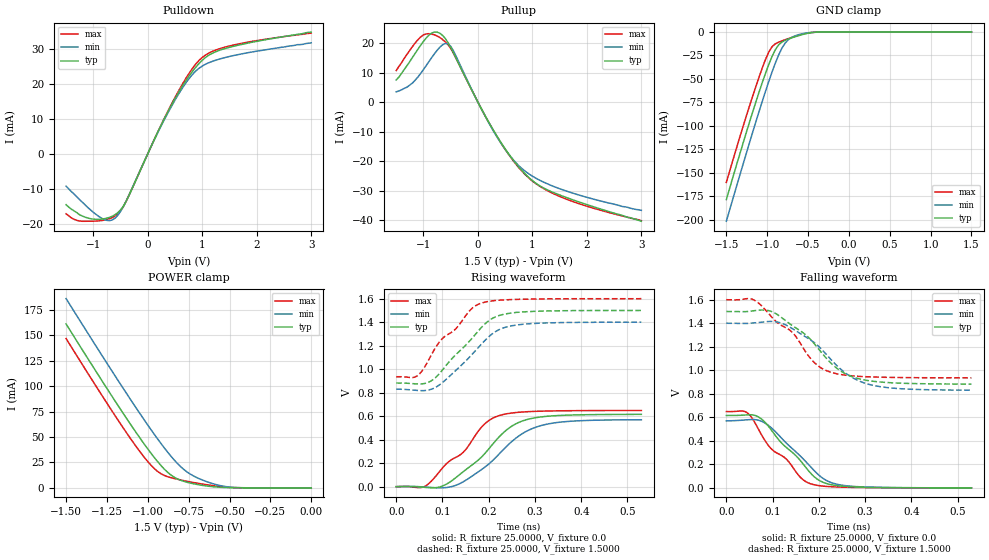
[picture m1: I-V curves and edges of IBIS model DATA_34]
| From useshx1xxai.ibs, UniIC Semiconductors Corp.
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|When TDQS is enabled, NU_TDQS is a output with terminal resistance;
|When TDQS is disabled, NU_TDQS is a DM;
|   Model DATA_34
[Model]  DATA_34
Model_type   I/O
Polarity   Non-Inverting
Enable   Active-High
Vinl =   0.600000V
Vinh =   0.900000V
Vmeas =   0.750000V
Rref =   25.0000000
Vref =   0.7500000V
C_comp   1.3900pF   1.3640pF   1.5600pF
[Temperature Range]   25.0000   95.0000   -40.0000
[Voltage Range]   1.5000V   1.4000V   1.6000V
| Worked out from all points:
|   slope of the pulldown table from 0 to 0.225 V, typ, clamps not added: 29.8 ohm
|   slope of the pullup table from 0 to 0.225 V, typ, clamps not added: 29.6 ohm
|   GND clamp passes 1 mA (typ) near -0.48 V on its own axis
|   POWER clamp passes 1 mA (typ) near -0.59 V on its own axis
|   rising waveform, R_fixture 25.0000, V_fixture 0.0: 20-80 % time 98.2ps typ, 102ps min, 93.5ps max; typ from 0 V to 0.615 V
|   rising waveform, R_fixture 25.0000, V_fixture 1.5000: 20-80 % time 86.9ps typ, 86.6ps min, 83.7ps max; typ from 0.882 V to 1.5 V
|   falling waveform, R_fixture 25.0000, V_fixture 0.0: 20-80 % time 85.5ps typ, 86.9ps min, 85ps max; typ from 0.615 V to 0 V
|   falling waveform, R_fixture 25.0000, V_fixture 1.5000: 20-80 % time 99ps typ, 99.1ps min, 94.7ps max; typ from 1.5 V to 0.882 V
[Pulldown]
|Voltage   I(typ)   I(min)   I(max)
-1.5V     -14.6mA    -9.3mA     -17.2mA
-1.3V     -16.9mA    -12.4mA    -19.1mA
-1.1V     -18.42mA   -15.42mA   -19.33mA
-850mV    -18.72mA   -18.45mA   -19.14mA
-650mV    -17.88mA   -18.95mA   -18.26mA
-400mV    -13.69mA   -13.63mA   -13.73mA
150mV     5.101mA    4.945mA    5.116mA
500mV     15.78mA    15.34mA    16.1mA
750mV     22.05mA    21.34mA    22.8mA
950mV     25.95mA    24.55mA    26.84mA
1.45V     30.22mA    27.62mA    30.62mA
3V        34.8mA     31.7mA     34.5mA
[Pullup]
|Voltage   I(typ)   I(min)   I(max)
-1.5V     7.5mA      3.5mA      10.7mA
-1.2V     15.18mA    6.5mA      18.86mA
-1V       20.55mA    11.03mA    22.75mA
-750mV    23.71mA    17.52mA    22.4mA
-550mV    20.17mA    19.79mA    19.47mA
-450mV    16.69mA    17.37mA    16.58mA
300mV     -9.979mA   -10.24mA   -10.09mA
550mV     -17.14mA   -17.23mA   -17.31mA
800mV     -23mA      -22.34mA   -23.2mA
1.1V      -27.91mA   -26.09mA   -28.02mA
1.55V     -31.76mA   -29.61mA   -32.28mA
3V        -40.3mA    -36.6mA    -40.1mA
[GND_clamp]
|Voltage   I(typ)   I(min)   I(max)
-1.5V     -178.7mA   -201.8mA   -160.4mA
-1.22V    -97.06mA   -119mA     -79.82mA
-1.1V     -64.25mA   -84.88mA   -48.13mA
-1.02V    -43.87mA   -63.01mA   -29.1mA
-980mV    -34.46mA   -52.52mA   -21.22mA
-940mV    -25.94mA   -42.47mA   -15.57mA
-900mV    -18.8mA    -33.04mA   -12.54mA
-820mV    -10.64mA   -17.25mA   -9.468mA
-740mV    -7.413mA   -8.071mA   -6.938mA
-620mV    -3.934mA   -2.917mA   -3.522mA
-420mV    -302.4uA   -187.9uA   -208.3uA
1.5V      1.623nA    17.64nA    235.2pA
[POWER_clamp]
|Voltage   I(typ)   I(min)   I(max)
-1.5V     161.3mA    186.3mA    147mA
-1.22V    90.37mA    115.2mA    75.9mA
-1.04V    47.2mA     71.18mA    33.88mA
-980mV    33.96mA    57.17mA    22.22mA
-940mV    25.82mA    48.16mA    16.16mA
-880mV    15.49mA    35.42mA    11.04mA
-840mV    10.61mA    27.72mA    9.264mA
-780mV    6.409mA    18.15mA    7.115mA
-720mV    3.991mA    11.66mA    5.224mA
-560mV    586.1uA    2.318mA    1.296mA
-440mV    47uA       184.9uA    109.8uA
0V        1.623nA    5.301nA    289pA
[Ramp]
| variable   typ   min   max
dV/dt_r  0.3694/99.9524p   0.3422/0.1029n   0.3891/94.7830p
dV/dt_f  0.3712/0.1005n   0.3425/0.1006n   0.3991/96.2412p
R_load = 25.0000
[Rising Waveform]
R_fixture= 25.0000
V_fixture= 0.0
V_fixture_min= 0.0
V_fixture_max= 0.0
|time   V(typ)   V(min)   V(max)
0s        0V         0V         0V
60ps      -5.059mV   -2.656mV   -859.5uV
105ps     13.96mV    -8.608mV   181.2mV
150ps     143.2mV    53.69mV    314.4mV
190ps     275.1mV    161.4mV    529.6mV
225ps     433.6mV    288.3mV    607.6mV
265ps     546.6mV    431.1mV    632.9mV
320ps     596.5mV    526.6mV    643mV
390ps     610.7mV    559.7mV    646.7mV
530ps     615.1mV    569.3mV    648.3mV
[Rising Waveform]
R_fixture= 25.0000
V_fixture= 1.5000
V_fixture_min= 1.4000
V_fixture_max= 1.6000
|time   V(typ)   V(min)   V(max)
0s        882.1mV    830.4mV    935.2mV
45ps      874mV      819mV      941.6mV
75ps      898.8mV    827.8mV    1.114V
100ps     992.8mV    885.7mV    1.261V
130ps     1.127V     993.3mV    1.348V
165ps     1.267V     1.13V      1.521V
185ps     1.358V     1.216V     1.563V
220ps     1.453V     1.331V     1.586V
265ps     1.484V     1.378V     1.594V
530ps     1.5V       1.4V       1.6V
[Falling Waveform]
R_fixture= 25.0000
V_fixture= 0.0
V_fixture_min= 0.0
V_fixture_max= 0.0
|time   V(typ)   V(min)   V(max)
0s        615.1mV    569.3mV    648.3mV
45ps      620.4mV    578.5mV    638.9mV
75ps      588.4mV    567.5mV    458.6mV
100ps     477.1mV    500.9mV    321mV
130ps     342.3mV    379.5mV    243.2mV
165ps     207.8mV    250.9mV    71.54mV
185ps     113.1mV    167mV      31.06mV
215ps     38.58mV    65.59mV    12.58mV
255ps     12.74mV    19.75mV    5.325mV
530ps     0V         0V         0V
[Falling Waveform]
R_fixture= 25.0000
V_fixture= 1.5000
V_fixture_min= 1.4000
V_fixture_max= 1.6000
|time   V(typ)   V(min)   V(max)
0s        1.5V       1.4V       1.6V
55ps      1.503V     1.401V     1.605V
100ps     1.496V     1.414V     1.444V
145ps     1.373V     1.348V     1.312V
180ps     1.27V      1.263V     1.11V
205ps     1.154V     1.182V     1.019V
225ps     1.065V     1.096V     984.1mV
270ps     948mV      943mV      952.8mV
315ps     907.3mV    873.4mV    942.9mV
530ps     882.1mV    830.4mV    935.2mV
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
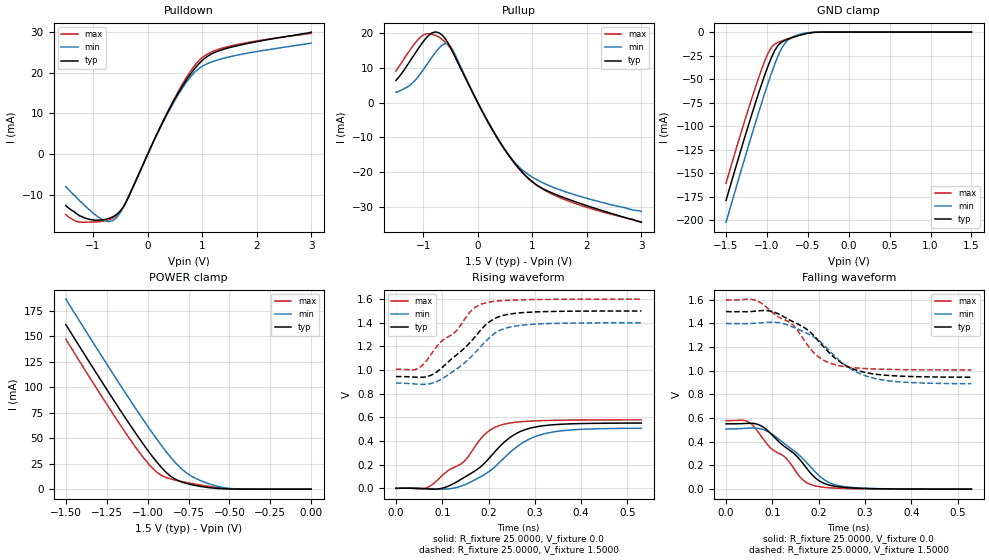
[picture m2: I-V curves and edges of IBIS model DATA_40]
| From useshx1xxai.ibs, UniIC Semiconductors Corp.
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|   Model DATA_40
[Model]  DATA_40
Model_type   I/O
Polarity   Non-Inverting
Enable   Active-High
Vinl =   0.600000V
Vinh =   0.900000V
Vmeas =   0.750000V
Rref =   25.000000
Vref =   0.7500000V
C_comp   1.3900pF   1.3640pF   1.5600pF
[Temperature Range]   25.0000   95.0000   -40.0000
[Voltage Range]   1.5000V   1.4000V   1.6000V
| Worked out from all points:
|   slope of the pulldown table from 0 to 0.225 V, typ, clamps not added: 34.7 ohm
|   slope of the pullup table from 0 to 0.225 V, typ, clamps not added: 34.4 ohm
|   GND clamp passes 1 mA (typ) near -0.48 V on its own axis
|   POWER clamp passes 1 mA (typ) near -0.59 V on its own axis
|   rising waveform, R_fixture 25.0000, V_fixture 0.0: 20-80 % time 95.5ps typ, 98.7ps min, 91.8ps max; typ from 0 V to 0.552 V
|   rising waveform, R_fixture 25.0000, V_fixture 1.5000: 20-80 % time 86.4ps typ, 84.2ps min, 83.3ps max; typ from 0.946 V to 1.5 V
|   falling waveform, R_fixture 25.0000, V_fixture 0.0: 20-80 % time 85.1ps typ, 85.4ps min, 84ps max; typ from 0.552 V to 0 V
|   falling waveform, R_fixture 25.0000, V_fixture 1.5000: 20-80 % time 95.2ps typ, 95.9ps min, 93.6ps max; typ from 1.5 V to 0.946 V
[Pulldown]
|Voltage   I(typ)   I(min)   I(max)
-1.5V     -12.5mA    -7.9mA     -14.7mA
-1.3V     -14.5mA    -10.6mA    -16.4mA
-1.1V     -15.78mA   -13.18mA   -16.57mA
-800mV    -15.97mA   -16.14mA   -16.3mA
-650mV    -15.34mA   -16.26mA   -15.66mA
-400mV    -11.78mA   -11.73mA   -11.82mA
150mV     4.391mA    4.256mA    4.404mA
500mV     13.57mA    13.19mA    13.85mA
750mV     18.96mA    18.34mA    19.61mA
950mV     22.29mA    21.08mA    23.05mA
1.45V     25.92mA    23.69mA    26.26mA
3V        29.9mA     27.2mA     29.6mA
[Pullup]
|Voltage   I(typ)   I(min)   I(max)
-1.5V     6.4mA      3mA        9.1mA
-1.25V    11.77mA    4.9mA      15.01mA
-1V       17.56mA    9.42mA     19.48mA
-750mV    20.34mA    14.97mA    19.23mA
-550mV    17.36mA    16.99mA    16.74mA
-450mV    14.37mA    14.95mA    14.28mA
300mV     -8.588mA   -8.811mA   -8.682mA
550mV     -14.74mA   -14.81mA   -14.89mA
800mV     -19.76mA   -19.19mA   -19.93mA
1.1V      -23.96mA   -22.39mA   -24.05mA
1.55V     -27.24mA   -25.4mA    -27.69mA
3V        -34.5mA    -31.4mA    -34.4mA
[GND_clamp]
|Voltage   I(typ)   I(min)   I(max)
-1.5V     -178.7mA   -201.8mA   -160.4mA
-1.22V    -97.06mA   -119mA     -79.82mA
-1.1V     -64.25mA   -84.88mA   -48.13mA
-1.02V    -43.87mA   -63.01mA   -29.1mA
-980mV    -34.46mA   -52.52mA   -21.22mA
-940mV    -25.94mA   -42.47mA   -15.57mA
-900mV    -18.8mA    -33.04mA   -12.54mA
-820mV    -10.64mA   -17.25mA   -9.468mA
-740mV    -7.413mA   -8.071mA   -6.938mA
-620mV    -3.934mA   -2.917mA   -3.522mA
-420mV    -302.4uA   -187.9uA   -208.3uA
1.5V      1.623nA    17.64nA    235.2pA
[POWER_clamp]
|Voltage   I(typ)   I(min)   I(max)
-1.5V     161.3mA    186.3mA    147mA
-1.22V    90.37mA    115.2mA    75.9mA
-1.04V    47.2mA     71.18mA    33.88mA
-980mV    33.96mA    57.17mA    22.22mA
-940mV    25.82mA    48.16mA    16.16mA
-880mV    15.49mA    35.42mA    11.04mA
-840mV    10.61mA    27.72mA    9.264mA
-780mV    6.409mA    18.15mA    7.115mA
-720mV    3.991mA    11.66mA    5.224mA
-560mV    586.1uA    2.318mA    1.296mA
-440mV    47uA       184.9uA    109.8uA
0V        1.623nA    5.301nA    289pA
[Ramp]
| variable   typ   min   max
dV/dt_r  0.3315/96.9880p   0.3052/0.1003n   0.3475/92.8356p
dV/dt_f  0.3332/96.7909p   0.3063/97.5091p   0.3558/94.0132p
R_load = 25.0000
[Rising Waveform]
R_fixture= 25.0000
V_fixture= 0.0
V_fixture_min= 0.0
V_fixture_max= 0.0
|time   V(typ)   V(min)   V(max)
0s        0V         0V         0V
65ps      -4.097mV   -2.199mV   2.93mV
115ps     21.52mV    -3.854mV   155.7mV
145ps     86.52mV    24.7mV     219.7mV
180ps     172.9mV    91.67mV    404mV
200ps     248.7mV    139.2mV    483.1mV
230ps     376mV      243.1mV    538.4mV
270ps     482.4mV    375.4mV    563mV
325ps     532.1mV    465.2mV    573.4mV
530ps     551.8mV    507.6mV    578.9mV
[Rising Waveform]
R_fixture= 25.0000
V_fixture= 1.5000
V_fixture_min= 1.4000
V_fixture_max= 1.6000
|time   V(typ)   V(min)   V(max)
0s        945.6mV    890.9mV    1.007V
45ps      939mV      880.9mV    1.009V
60ps      940mV      878.5mV    1.051V
80ps      963.9mV    890.6mV    1.155V
140ps     1.157V     1.034V     1.38V
165ps     1.254V     1.123V     1.511V
190ps     1.367V     1.227V     1.564V
225ps     1.454V     1.336V     1.586V
265ps     1.482V     1.376V     1.593V
530ps     1.5V       1.4V       1.6V
[Falling Waveform]
R_fixture= 25.0000
V_fixture= 0.0
V_fixture_min= 0.0
V_fixture_max= 0.0
|time   V(typ)   V(min)   V(max)
0s        551.8mV    507.6mV    578.9mV
45ps      555.8mV    514.8mV    574.8mV
80ps      525.2mV    503.7mV    425.6mV
100ps     456.3mV    463.1mV    335.6mV
130ps     349.4mV    372.6mV    261.2mV
165ps     222.5mV    260.5mV    81.43mV
190ps     105.4mV    156.3mV    30.23mV
220ps     37.91mV    61.29mV    12.82mV
260ps     13.05mV    19.41mV    5.506mV
530ps     0V         0V         0V
[Falling Waveform]
R_fixture= 25.0000
V_fixture= 1.5000
V_fixture_min= 1.4000
V_fixture_max= 1.6000
|time   V(typ)   V(min)   V(max)
0s        1.5V       1.4V       1.6V
65ps      1.504V     1.402V     1.594V
110ps     1.486V     1.408V     1.463V
145ps     1.414V     1.368V     1.386V
175ps     1.348V     1.316V     1.222V
200ps     1.251V     1.257V     1.117V
230ps     1.126V     1.143V     1.057V
270ps     1.022V     1.014V     1.028V
325ps     970.3mV    931.9mV    1.015V
530ps     945.6mV    890.9mV    1.007V
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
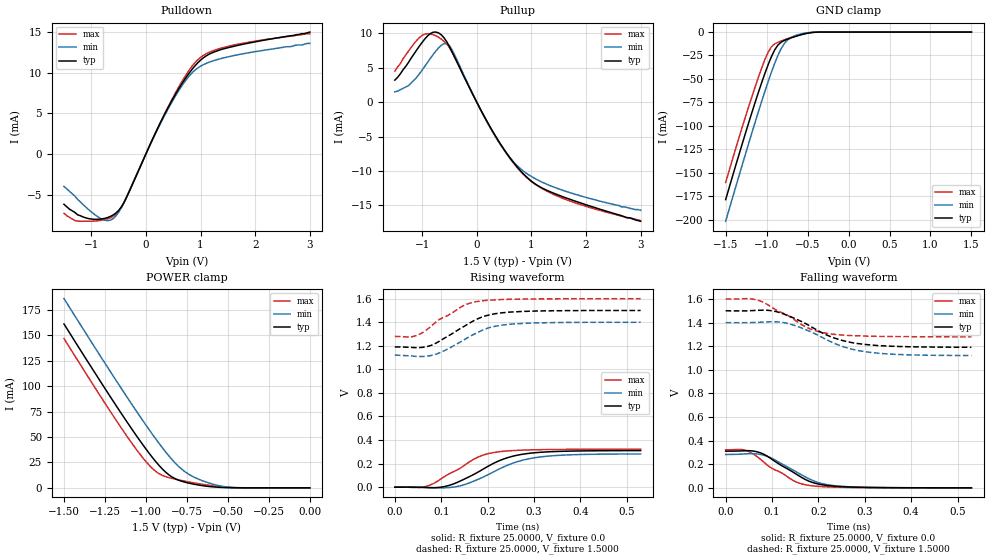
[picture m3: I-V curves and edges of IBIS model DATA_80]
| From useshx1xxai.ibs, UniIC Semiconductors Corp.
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|   Model DATA_80
[Model]  DATA_80
Model_type   I/O
Polarity   Non-Inverting
Enable   Active-High
Vinl =   0.600000V
Vinh =   0.900000V
Vmeas =   0.750000V
Rref =   25.000000
Vref =   0.7500000V
C_comp   1.3900pF   1.3640pF   1.5600pF
[Temperature Range]   25.0000   95.0000   -40.0000
[Voltage Range]   1.5000V   1.4000V   1.6000V
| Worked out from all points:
|   slope of the pulldown table from 0 to 0.225 V, typ, clamps not added: 68.5 ohm
|   slope of the pullup table from 0 to 0.225 V, typ, clamps not added: 67.8 ohm
|   GND clamp passes 1 mA (typ) near -0.48 V on its own axis
|   POWER clamp passes 1 mA (typ) near -0.59 V on its own axis
|   rising waveform, R_fixture 25.0000, V_fixture 0.0: 20-80 % time 95.2ps typ, 98.9ps min, 83.7ps max; typ from 0 V to 0.311 V
|   rising waveform, R_fixture 25.0000, V_fixture 1.5000: 20-80 % time 82.7ps typ, 80.9ps min, 74.6ps max; typ from 1.19 V to 1.5 V
|   falling waveform, R_fixture 25.0000, V_fixture 0.0: 20-80 % time 79.2ps typ, 80.1ps min, 74.6ps max; typ from 0.311 V to 0 V
|   falling waveform, R_fixture 25.0000, V_fixture 1.5000: 20-80 % time 101ps typ, 101ps min, 87.3ps max; typ from 1.5 V to 1.19 V
[Pulldown]
|Voltage   I(typ)   I(min)   I(max)
-1.5V     -6.2mA     -4mA       -7.3mA
-1.3V     -7.2mA     -5.2mA     -8.2mA
-1.05V    -7.96mA    -6.85mA    -8.28mA
-800mV    -7.989mA   -8.05mA    -8.161mA
-600mV    -7.517mA   -7.961mA   -7.671mA
-400mV    -5.963mA   -5.942mA   -5.982mA
100mV     1.497mA    1.449mA    1.498mA
450mV     6.253mA    6.074mA    6.364mA
750mV     9.561mA    9.241mA    9.895mA
950mV     11.22mA    10.58mA    11.59mA
1.4V      12.89mA    11.78mA    13.06mA
3V        15mA       13.6mA     14.8mA
[Pullup]
|Voltage   I(typ)   I(min)   I(max)
-1.5V     3.2mA      1.5mA      4.5mA
-1.25V    5.77mA     2.4mA      7.43mA
-1V       8.69mA     4.66mA     9.7mA
-750mV    10.19mA    7.42mA     9.651mA
-550mV    8.786mA    8.526mA    8.446mA
-450mV    7.293mA    7.583mA    7.236mA
300mV     -4.346mA   -4.459mA   -4.394mA
550mV     -7.444mA   -7.477mA   -7.522mA
800mV     -9.959mA   -9.656mA   -10.05mA
1.1V      -12.03mA   -11.24mA   -12.08mA
1.55V     -13.66mA   -12.73mA   -13.89mA
3V        -17.3mA    -15.7mA    -17.2mA
[GND_clamp]
|Voltage   I(typ)   I(min)   I(max)
-1.5V     -178.7mA   -201.8mA   -160.4mA
-1.22V    -97.06mA   -119mA     -79.82mA
-1.1V     -64.25mA   -84.88mA   -48.13mA
-1.02V    -43.87mA   -63.01mA   -29.1mA
-980mV    -34.46mA   -52.52mA   -21.22mA
-940mV    -25.94mA   -42.47mA   -15.57mA
-900mV    -18.8mA    -33.04mA   -12.54mA
-820mV    -10.64mA   -17.25mA   -9.468mA
-740mV    -7.413mA   -8.071mA   -6.938mA
-620mV    -3.934mA   -2.917mA   -3.522mA
-420mV    -302.4uA   -187.9uA   -208.3uA
1.5V      1.623nA    17.64nA    235.2pA
[POWER_clamp]
|Voltage   I(typ)   I(min)   I(max)
-1.5V     161.3mA    186.3mA    147mA
-1.22V    90.37mA    115.2mA    75.9mA
-1.04V    47.2mA     71.18mA    33.88mA
-980mV    33.96mA    57.17mA    22.22mA
-940mV    25.82mA    48.16mA    16.16mA
-880mV    15.49mA    35.42mA    11.04mA
-840mV    10.61mA    27.72mA    9.264mA
-780mV    6.409mA    18.15mA    7.115mA
-720mV    3.991mA    11.66mA    5.224mA
-560mV    586.1uA    2.318mA    1.296mA
-440mV    47uA       184.9uA    109.8uA
0V        1.623nA    5.301nA    289pA
[Ramp]
| variable   typ   min   max
dV/dt_r  0.1867/96.3613p   0.1696/99.8013p   0.1936/84.4618p
dV/dt_f  0.1860/0.1017n   0.1680/0.1020n   0.1926/87.7808p
R_load = 25.0000
[Rising Waveform]
R_fixture= 25.0000
V_fixture= 0.0
V_fixture_min= 0.0
V_fixture_max= 0.0
|time   V(typ)   V(min)   V(max)
0s        0V         0V         0V
65ps      -2.457mV   -1.226mV   4.844mV
85ps      -4.334mV   -3.958mV   34.52mV
110ps     8.321mV    -4.497mV   97.64mV
140ps     50.43mV    10.73mV    158.9mV
175ps     118.5mV    59.16mV    247.3mV
215ps     206.5mV    134.4mV    295.3mV
265ps     272.2mV    217.6mV    313mV
315ps     296.5mV    257.4mV    318.6mV
530ps     310.6mV    282.1mV    322.5mV
[Rising Waveform]
R_fixture= 25.0000
V_fixture= 1.5000
V_fixture_min= 1.4000
V_fixture_max= 1.6000
|time   V(typ)   V(min)   V(max)
0s        1.19V      1.12V      1.279V
40ps      1.185V     1.112V     1.279V
55ps      1.185V     1.109V     1.301V
75ps      1.199V     1.115V     1.355V
100ps     1.248V     1.146V     1.431V
145ps     1.355V     1.241V     1.534V
175ps     1.422V     1.306V     1.574V
210ps     1.467V     1.36V      1.588V
255ps     1.487V     1.385V     1.595V
530ps     1.5V       1.4V       1.6V
[Falling Waveform]
R_fixture= 25.0000
V_fixture= 0.0
V_fixture_min= 0.0
V_fixture_max= 0.0
|time   V(typ)   V(min)   V(max)
0s        310.6mV    282.1mV    322.5mV
40ps      313.7mV    286.9mV    321.1mV
55ps      313.7mV    289.5mV    296.5mV
75ps      296.2mV    282.6mV    242.5mV
95ps      254.5mV    258.6mV    177mV
145ps     133.7mV    151.2mV    63.43mV
180ps     55.93mV    76.02mV    20.51mV
215ps     21.84mV    29.56mV    8.771mV
260ps     8.103mV    10.24mV    3.659mV
530ps     0V         0V         0V
[Falling Waveform]
R_fixture= 25.0000
V_fixture= 1.5000
V_fixture_min= 1.4000
V_fixture_max= 1.6000
|time   V(typ)   V(min)   V(max)
0s        1.5V       1.4V       1.6V
65ps      1.503V     1.401V     1.593V
110ps     1.492V     1.406V     1.504V
140ps     1.45V      1.386V     1.446V
175ps     1.386V     1.336V     1.359V
215ps     1.3V       1.26V      1.311V
265ps     1.236V     1.182V     1.291V
310ps     1.211V     1.148V     1.285V
390ps     1.196V     1.127V     1.281V
530ps     1.19V      1.12V      1.279V
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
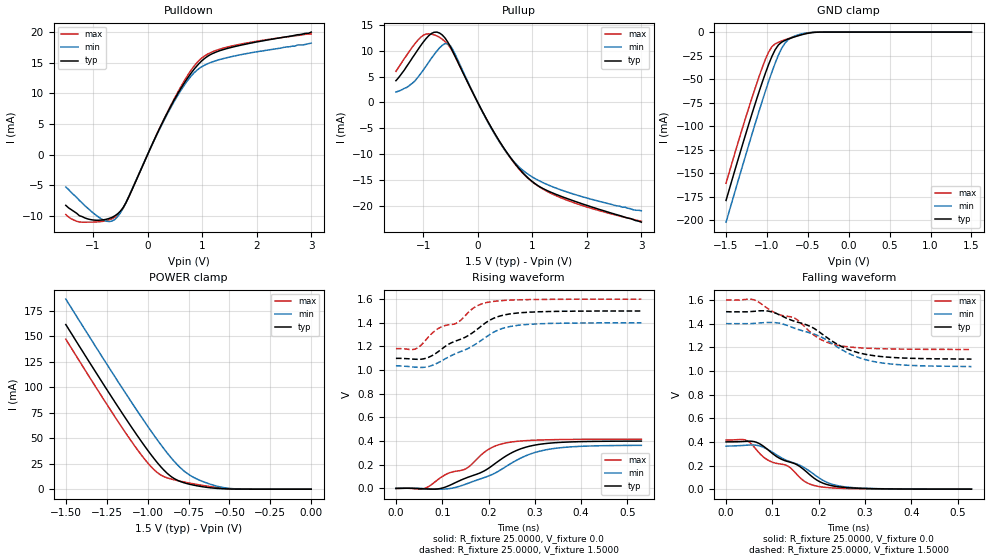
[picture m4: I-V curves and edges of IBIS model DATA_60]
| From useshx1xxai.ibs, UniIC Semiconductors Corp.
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|   Model DATA_60
[Model]  DATA_60
Model_type   I/O
Polarity   Non-Inverting
Enable   Active-High
Vinl =   0.600000V
Vinh =   0.900000V
Vmeas =   0.750000V
Rref =   25.000000
Vref =   0.7500000V
C_comp   1.3900pF   1.3640pF   1.5600pF
[Temperature Range]   25.0000   95.0000   -40.0000
[Voltage Range]   1.5000V   1.4000V   1.6000V
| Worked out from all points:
|   slope of the pulldown table from 0 to 0.225 V, typ, clamps not added: 51.6 ohm
|   slope of the pullup table from 0 to 0.225 V, typ, clamps not added: 51.1 ohm
|   GND clamp passes 1 mA (typ) near -0.48 V on its own axis
|   POWER clamp passes 1 mA (typ) near -0.59 V on its own axis
|   rising waveform, R_fixture 25.0000, V_fixture 0.0: 20-80 % time 114ps typ, 114ps min, 107ps max; typ from 0 V to 0.4 V
|   rising waveform, R_fixture 25.0000, V_fixture 1.5000: 20-80 % time 103ps typ, 102ps min, 97.8ps max; typ from 1.1 V to 1.5 V
|   falling waveform, R_fixture 25.0000, V_fixture 0.0: 20-80 % time 100ps typ, 101ps min, 98.1ps max; typ from 0.4 V to 0 V
|   falling waveform, R_fixture 25.0000, V_fixture 1.5000: 20-80 % time 117ps typ, 114ps min, 110ps max; typ from 1.5 V to 1.1 V
[Pulldown]
|Voltage   I(typ)   I(min)   I(max)
-1.5V     -8.3mA     -5.3mA     -9.8mA
-1.3V     -9.6mA     -7mA       -10.9mA
-1.05V    -10.62mA   -9.15mA    -11.04mA
-800mV    -10.65mA   -10.74mA   -10.88mA
-600mV    -10.01mA   -10.6mA    -10.22mA
-400mV    -7.919mA   -7.889mA   -7.943mA
450mV     8.306mA    8.07mA     8.453mA
750mV     12.71mA    12.29mA    13.15mA
950mV     14.92mA    14.09mA    15.43mA
1.15V     16.31mA    15.01mA    16.62mA
1.45V     17.3mA     15.81mA    17.53mA
3V        20mA       18.2mA     19.7mA
[Pullup]
|Voltage   I(typ)   I(min)   I(max)
-1.5V     4.2mA      2mA        6mA
-1.2V     8.58mA     3.7mA      10.67mA
-1V       11.63mA    6.23mA     12.95mA
-750mV    13.58mA    9.92mA     12.85mA
-550mV    11.67mA    11.36mA    11.23mA
-450mV    9.677mA    10.06mA    9.603mA
300mV     -5.771mA   -5.921mA   -5.835mA
550mV     -9.892mA   -9.938mA   -9.995mA
800mV     -13.24mA   -12.85mA   -13.36mA
1.1V      -16.02mA   -14.96mA   -16.09mA
1.55V     -18.2mA    -16.96mA   -18.5mA
3V        -23.1mA    -20.9mA    -22.9mA
[GND_clamp]
|Voltage   I(typ)   I(min)   I(max)
-1.5V     -178.7mA   -201.8mA   -160.4mA
-1.22V    -97.06mA   -119mA     -79.82mA
-1.1V     -64.25mA   -84.88mA   -48.13mA
-1.02V    -43.87mA   -63.01mA   -29.1mA
-980mV    -34.46mA   -52.52mA   -21.22mA
-940mV    -25.94mA   -42.47mA   -15.57mA
-900mV    -18.8mA    -33.04mA   -12.54mA
-820mV    -10.64mA   -17.25mA   -9.468mA
-740mV    -7.413mA   -8.071mA   -6.938mA
-620mV    -3.934mA   -2.917mA   -3.522mA
-420mV    -302.4uA   -187.9uA   -208.3uA
1.5V      1.623nA    17.64nA    235.2pA
[POWER_clamp]
|Voltage   I(typ)   I(min)   I(max)
-1.5V     161.3mA    186.3mA    147mA
-1.22V    90.37mA    115.2mA    75.9mA
-1.04V    47.2mA     71.18mA    33.88mA
-980mV    33.96mA    57.17mA    22.22mA
-940mV    25.82mA    48.16mA    16.16mA
-880mV    15.49mA    35.42mA    11.04mA
-840mV    10.61mA    27.72mA    9.264mA
-780mV    6.409mA    18.15mA    7.115mA
-720mV    3.991mA    11.66mA    5.224mA
-560mV    586.1uA    2.318mA    1.296mA
-440mV    47uA       184.9uA    109.8uA
0V        1.623nA    5.301nA    289pA
[Ramp]
| variable   typ   min   max
dV/dt_r  0.2403/0.1158n   0.2188/0.1157n   0.2496/0.1087n
dV/dt_f  0.2406/0.1185n   0.2184/0.1147n   0.2514/0.1118n
R_load = 25.0000
[Rising Waveform]
R_fixture= 25.0000
V_fixture= 0.0
V_fixture_min= 0.0
V_fixture_max= 0.0
|time   V(typ)   V(min)   V(max)
0s        0V         0V         0V
60ps      -3.534mV   -1.847mV   -2.696mV
100ps     2.819mV    -6.156mV   100.1mV
150ps     85.75mV    34.76mV    163.8mV
195ps     157.5mV    97.5mV     317.3mV
235ps     267mV      178.1mV    382.2mV
280ps     347.7mV    274.9mV    403.4mV
335ps     383.4mV    333.5mV    411.3mV
405ps     395.7mV    356.4mV    414.6mV
530ps     399.8mV    363.7mV    415.8mV
[Rising Waveform]
R_fixture= 25.0000
V_fixture= 1.5000
V_fixture_min= 1.4000
V_fixture_max= 1.6000
|time   V(typ)   V(min)   V(max)
0s        1.099V     1.036V     1.181V
40ps      1.092V     1.025V     1.176V
70ps      1.107V     1.029V     1.279V
95ps      1.166V     1.07V      1.359V
135ps     1.254V     1.149V     1.406V
170ps     1.328V     1.214V     1.531V
200ps     1.415V     1.293V     1.574V
230ps     1.462V     1.352V     1.587V
275ps     1.486V     1.383V     1.594V
530ps     1.5V       1.4V       1.6V
[Falling Waveform]
R_fixture= 25.0000
V_fixture= 0.0
V_fixture_min= 0.0
V_fixture_max= 0.0
|time   V(typ)   V(min)   V(max)
0s        399.8mV    363.7mV    415.8mV
40ps      403.9mV    370.5mV    417.3mV
65ps      397.1mV    371.5mV    335.9mV
90ps      334.7mV    335.7mV    246.7mV
135ps     231.8mV    236.7mV    191.8mV
170ps     158.9mV    179.4mV    64.77mV
195ps     79.5mV     111mV      26.57mV
225ps     32.02mV    46.64mV    11.69mV
270ps     10.57mV    14.32mV    4.595mV
530ps     0V         0V         0V
[Falling Waveform]
R_fixture= 25.0000
V_fixture= 1.5000
V_fixture_min= 1.4000
V_fixture_max= 1.6000
|time   V(typ)   V(min)   V(max)
0s        1.5V       1.4V       1.6V
60ps      1.503V     1.401V     1.601V
100ps     1.497V     1.409V     1.503V
150ps     1.417V     1.358V     1.442V
180ps     1.379V     1.322V     1.334V
200ps     1.333V     1.296V     1.275V
240ps     1.226V     1.202V     1.217V
290ps     1.149V     1.108V     1.195V
340ps     1.119V     1.065V     1.187V
530ps     1.099V     1.036V     1.181V
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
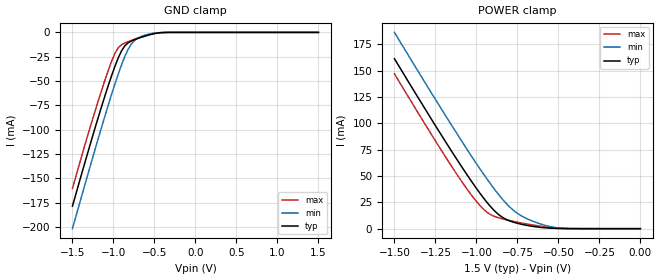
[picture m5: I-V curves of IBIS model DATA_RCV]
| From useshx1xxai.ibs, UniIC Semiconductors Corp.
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|   Model DATA_RCV
[Model]  DATA_RCV
Model_type   Input
Polarity   Non-Inverting
Vinl =   0.600000V
Vinh =   0.900000V
C_comp   1.3900pF   1.3640pF   1.5600pF
[Temperature Range]   25.0000   95.0000   -40.0000
[Voltage Range]   1.5000V   1.4000V   1.6000V
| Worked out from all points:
|   GND clamp passes 1 mA (typ) near -0.48 V on its own axis
|   POWER clamp passes 1 mA (typ) near -0.59 V on its own axis
[GND_clamp]
|Voltage   I(typ)   I(min)   I(max)
-1.5V     -178.7mA   -201.8mA   -160.4mA
-1.22V    -97.06mA   -119mA     -79.82mA
-1.1V     -64.25mA   -84.88mA   -48.13mA
-1.02V    -43.87mA   -63.01mA   -29.1mA
-980mV    -34.46mA   -52.52mA   -21.22mA
-940mV    -25.94mA   -42.47mA   -15.57mA
-900mV    -18.8mA    -33.04mA   -12.54mA
-820mV    -10.64mA   -17.25mA   -9.468mA
-740mV    -7.413mA   -8.071mA   -6.938mA
-620mV    -3.934mA   -2.917mA   -3.522mA
-420mV    -302.4uA   -187.9uA   -208.3uA
1.5V      1.623nA    17.64nA    235.2pA
[POWER_clamp]
|Voltage   I(typ)   I(min)   I(max)
-1.5V     161.3mA    186.3mA    147mA
-1.22V    90.37mA    115.2mA    75.9mA
-1.04V    47.2mA     71.18mA    33.88mA
-980mV    33.96mA    57.17mA    22.22mA
-940mV    25.82mA    48.16mA    16.16mA
-880mV    15.49mA    35.42mA    11.04mA
-840mV    10.61mA    27.72mA    9.264mA
-780mV    6.409mA    18.15mA    7.115mA
-720mV    3.991mA    11.66mA    5.224mA
-560mV    586.1uA    2.318mA    1.296mA
-440mV    47uA       184.9uA    109.8uA
0V        1.623nA    5.301nA    289pA
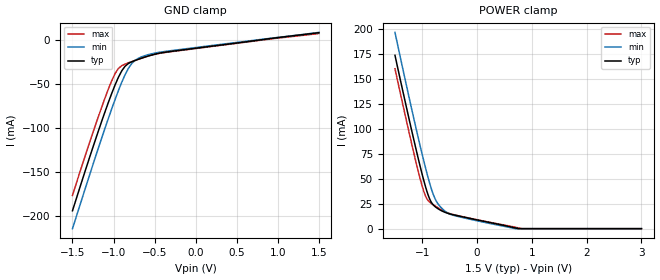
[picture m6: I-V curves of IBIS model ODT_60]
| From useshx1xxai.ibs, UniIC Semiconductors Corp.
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|   Model ODT_60
[Model]  ODT_60
Model_type   Input
Polarity   Non-Inverting
Vinl =   0.600000V
Vinh =   0.900000V
C_comp   1.3900pF   1.3640pF   1.5600pF
[Temperature Range]   25.0000   95.0000   -40.0000
[Voltage Range]   1.5000V   1.4000V   1.6000V
[GND_clamp]
|Voltage   I(typ)   I(min)   I(max)
-1.5V     -194.4mA   -214.8mA   -176.9mA
-1.22V    -113.2mA   -132.9mA   -96.59mA
-1.1V     -80.42mA   -99.14mA   -64.75mA
-1.02V    -60mA      -77.49mA   -45.61mA
-980mV    -50.55mA   -67.1mA    -37.67mA
-940mV    -41.97mA   -57.14mA   -31.97mA
-900mV    -34.78mA   -47.78mA   -28.87mA
-820mV    -26.46mA   -32.11mA   -25.65mA
-740mV    -23.04mA   -22.95mA   -22.93mA
-620mV    -19.15mA   -17.55mA   -19.13mA
-420mV    -14.26mA   -13.3mA    -14.51mA
1.5V      8.718mA    9.062mA    7.8mA
[POWER_clamp]
|Voltage   I(typ)   I(min)   I(max)
-1.5V     173.4mA    196.3mA    159.9mA
-1.14V    85.18mA    106.3mA    71.94mA
-1.04V    62.3mA     82.68mA    49.84mA
-960mV    45.41mA    64.67mA    35.15mA
-920mV    37.89mA    56.11mA    30.14mA
-860mV    28.89mA    44.19mA    26.25mA
-780mV    22.62mA    31.4mA     23.13mA
-700mV    19.44mA    23.75mA    20.41mA
-580mV    16.2mA     17.18mA    16.88mA
-320mV    12.49mA    11.79mA    12.65mA
752.8mV   0A         NA         NA
3V        0A         0A         0A
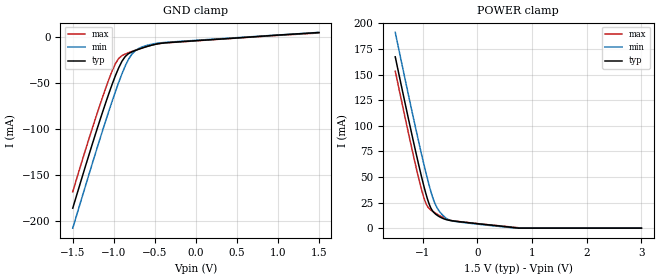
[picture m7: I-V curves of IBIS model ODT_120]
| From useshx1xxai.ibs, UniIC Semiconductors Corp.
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|   Model ODT_120
[Model]  ODT_120
Model_type   Input
Polarity   Non-Inverting
Vinl =   0.600000V
Vinh =   0.900000V
C_comp   1.3900pF   1.3640pF   1.5600pF
[Temperature Range]   25.0000   95.0000   -40.0000
[Voltage Range]   1.5000V   1.4000V   1.6000V
[GND_clamp]
|Voltage   I(typ)   I(min)   I(max)
-1.5V     -186.6mA   -208.3mA   -168.7mA
-1.22V    -105.1mA   -126mA     -88.2mA
-1.1V     -72.33mA   -92.01mA   -56.44mA
-1.02V    -51.93mA   -70.25mA   -37.36mA
-980mV    -42.51mA   -59.81mA   -29.45mA
-940mV    -33.96mA   -49.8mA    -23.78mA
-900mV    -26.79mA   -40.41mA   -20.71mA
-820mV    -18.55mA   -24.68mA   -17.56mA
-740mV    -15.23mA   -15.51mA   -14.94mA
-620mV    -11.55mA   -10.24mA   -11.34mA
-420mV    -7.291mA   -6.758mA   -7.373mA
1.5V      4.361mA    4.536mA    3.9mA
[POWER_clamp]
|Voltage   I(typ)   I(min)   I(max)
-1.5V     167.4mA    191.3mA    153.4mA
-1.14V    77.97mA    100.8mA    64.22mA
-1.04V    54.74mA    76.93mA    41.85mA
-960mV    37.6mA     58.64mA    27.05mA
-920mV    29.97mA    49.95mA    22.04mA
-860mV    20.85mA    37.82mA    18.17mA
-780mV    14.52mA    24.77mA    15.13mA
-700mV    11.4mA     16.89mA    12.54mA
-580mV    8.517mA    10.14mA    9.294mA
-400mV    6.754mA    6.47mA     6.839mA
752.9mV   0A         NA         NA
3V        0A         0A         0A
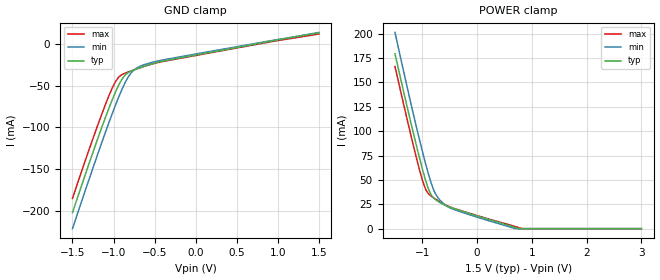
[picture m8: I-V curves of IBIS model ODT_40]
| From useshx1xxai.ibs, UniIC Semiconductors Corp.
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|   Model ODT_40
[Model]  ODT_40
Model_type   Input
Polarity   Non-Inverting
Vinl =   0.600000V
Vinh =   0.900000V
C_comp   1.3900pF   1.3640pF   1.5600pF
[Temperature Range]   25.0000   95.0000   -40.0000
[Voltage Range]   1.5000V   1.4000V   1.6000V
[GND_clamp]
|Voltage   I(typ)   I(min)   I(max)
-1.5V     -202.2mA   -221.3mA   -185.1mA
-1.22V    -121.3mA   -139.9mA   -105mA
-1.1V     -88.5mA    -106.3mA   -73.05mA
-1.02V    -68.05mA   -84.73mA   -53.86mA
-980mV    -58.58mA   -74.39mA   -45.89mA
-940mV    -49.98mA   -64.47mA   -40.16mA
-900mV    -42.75mA   -55.15mA   -37.02mA
-820mV    -34.35mA   -39.53mA   -33.73mA
-740mV    -30.83mA   -30.39mA   -30.92mA
-620mV    -26.73mA   -24.85mA   -26.92mA
-420mV    -21.2mA    -19.83mA   -21.63mA
1.5V      13.07mA    13.58mA    11.7mA
[POWER_clamp]
|Voltage   I(typ)   I(min)   I(max)
-1.5V     179.4mA    201.3mA    166.4mA
-1.14V    92.41mA    111.8mA    79.68mA
-1.04V    69.88mA    88.45mA    57.83mA
-960mV    53.23mA    70.7mA     43.25mA
-920mV    45.82mA    62.28mA    38.25mA
-860mV    36.94mA    50.57mA    34.33mA
-780mV    30.73mA    38.04mA    31.12mA
-700mV    27.46mA    30.62mA    28.27mA
-600mV    24.37mA    25.09mA    25.05mA
-240mV    17.27mA    16.15mA    17.54mA
752.8mV   0A         NA         NA
3V        0A         0A         0A
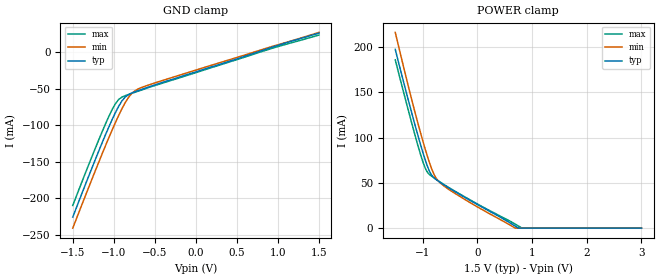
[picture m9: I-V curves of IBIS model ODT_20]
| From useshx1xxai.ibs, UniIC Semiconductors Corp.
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|   Model ODT_20
[Model]  ODT_20
Model_type   Input
Polarity   Non-Inverting
Vinl =   0.600000V
Vinh =   0.900000V
C_comp   1.3900pF   1.3640pF   1.5600pF
[Temperature Range]   25.0000   95.0000   -40.0000
[Voltage Range]   1.5000V   1.4000V   1.6000V
[GND_clamp]
|Voltage   I(typ)   I(min)   I(max)
-1.5V     -225.7mA   -240.8mA   -209.8mA
-1.18V    -134.4mA   -149.7mA   -119.1mA
-1.02V    -92.18mA   -106.5mA   -78.56mA
-980mV    -82.64mA   -96.28mA   -70.51mA
-940mV    -73.96mA   -86.48mA   -64.68mA
-900mV    -66.63mA   -77.27mA   -61.44mA
-860mV    -61.28mA   -68.92mA   -59.52mA
-820mV    -57.99mA   -61.81mA   -57.91mA
-740mV    -54.15mA   -52.67mA   -54.81mA
-460mV    -43.35mA   -40.68mA   -44.26mA
940mV     7.191mA    8.162mA    5.649mA
1.5V      26.1mA     27.08mA    23.4mA
[POWER_clamp]
|Voltage   I(typ)   I(min)   I(max)
-1.5V     197.5mA    216.3mA    185.9mA
-1.14V    114.2mA    128.2mA    103mA
-1.04V    92.71mA    105.8mA    81.87mA
-960mV    76.8mA     88.87mA    67.54mA
-880mV    63.62mA    73.33mA    59.56mA
-800mV    56.12mA    60.53mA    55.88mA
-740mV    53.14mA    54.1mA     53.4mA
-640mV    49mA       48.07mA    49.4mA
0V        26.1mA     23.52mA    26.74mA
600mV     5.719mA    3.337mA    7.644mA
752.6mV   0A         NA         NA
3V        0A         0A         0A
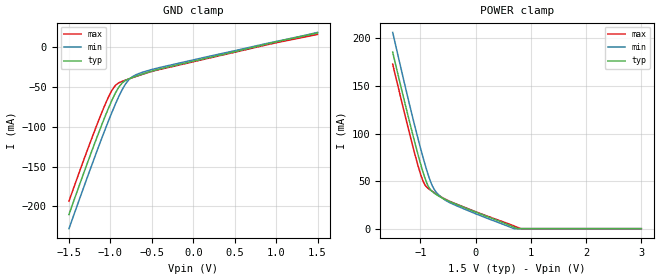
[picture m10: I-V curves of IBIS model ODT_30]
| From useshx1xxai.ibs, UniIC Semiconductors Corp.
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|   Model ODT_30
[Model]  ODT_30
Model_type   Input
Polarity   Non-Inverting
Vinl =   0.600000V
Vinh =   0.900000V
C_comp   1.3900pF   1.3640pF   1.5600pF
[Temperature Range]   25.0000   95.0000   -40.0000
[Voltage Range]   1.5000V   1.4000V   1.6000V
[GND_clamp]
|Voltage   I(typ)   I(min)   I(max)
-1.5V     -210.1mA   -227.8mA   -193.4mA
-1.22V    -129.3mA   -146.9mA   -113.3mA
-1.1V     -96.58mA   -113.4mA   -81.35mA
-1.02V    -76.1mA    -91.98mA   -62.1mA
-980mV    -66.61mA   -81.68mA   -54.1mA
-940mV    -57.98mA   -71.8mA    -48.34mA
-900mV    -50.72mA   -62.52mA   -45.17mA
-820mV    -42.24mA   -46.96mA   -41.8mA
-740mV    -38.61mA   -37.82mA   -38.89mA
-620mV    -34.31mA   -32.13mA   -34.69mA
-420mV    -28.12mA   -26.33mA   -28.72mA
1.5V      17.42mA    18.09mA    15.6mA
[POWER_clamp]
|Voltage   I(typ)   I(min)   I(max)
-1.5V     185.5mA    206.3mA    172.9mA
-1.14V    99.66mA    117.2mA    87.44mA
-1.04V    77.47mA    94.22mA    65.83mA
-960mV    61.07mA    76.75mA    51.34mA
-920mV    53.77mA    68.47mA    46.35mA
-860mV    45mA       56.97mA    42.4mA
-780mV    38.83mA    44.7mA     39.1mA
-700mV    35.46mA    37.49mA    36.12mA
-600mV    32.08mA    32.13mA    32.66mA
-20mV     17.88mA    16.17mA    18.29mA
752.7mV   0A         NA         NA
3V        0A         0A         0A
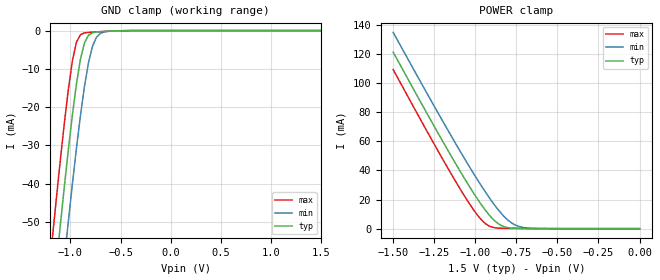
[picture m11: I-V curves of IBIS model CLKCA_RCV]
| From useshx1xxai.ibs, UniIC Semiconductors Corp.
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|   Model CLKCA_RCV
[Model]  CLKCA_RCV
Model_type   Input
Polarity   Non-Inverting
Vinl =   0.600000V
Vinh =   0.900000V
C_comp   0.9500pF   0.9400pF   0.9600pF
[Temperature Range]   25.0000   95.0000   -40.0000
[Voltage Range]   1.5000V   1.4000V   1.6000V
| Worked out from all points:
|   GND clamp passes 1 mA (typ) near -0.80 V on its own axis
|   POWER clamp passes 1 mA (typ) near -0.81 V on its own axis
[GND_clamp]
|Voltage   I(typ)   I(min)   I(max)
-1.5V     -160.2mA   -179.6mA   -143.2mA
-1.18V    -71.75mA   -91.32mA   -54.48mA
-1.1V     -50.85mA   -70.2mA    -33.88mA
-1.06V    -40.81mA   -59.91mA   -24.23mA
-1.02V    -31.17mA   -49.88mA   -15.38mA
-980mV    -22.15mA   -40.18mA   -7.971mA
-940mV    -14.08mA   -30.94mA   -3.07mA
-900mV    -7.546mA   -22.35mA   -1.096mA
-860mV    -3.248mA   -14.72mA   -611.7uA
-780mV    -591.5uA   -4.147mA   -406.4uA
-660mV    -225.7uA   -331.9uA   -232.2uA
1.5V      576.8pA    617.8pA    86.3pA
[POWER_clamp]
|Voltage   I(typ)   I(min)   I(max)
-1.5V     121.2mA    134.8mA    109.2mA
-1.18V    56.38mA    70.22mA    44.1mA
-1.08V    37.13mA    50.85mA    25.01mA
-1V       22.65mA    35.98mA    11.29mA
-960mV    15.99mA    28.87mA    5.747mA
-920mV    10.02mA    22.1mA     2.055mA
-860mV    3.386mA    12.92mA    376uA
-840mV    2.06mA     10.24mA    274.5uA
-800mV    675.4uA    5.743mA    195.2uA
-740mV    168.8uA    1.723mA    140.1uA
-660mV    60.96uA    258uA      85.71uA
0V        576.8pA    143pA      119.6pA
